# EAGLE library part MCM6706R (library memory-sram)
MEMORY

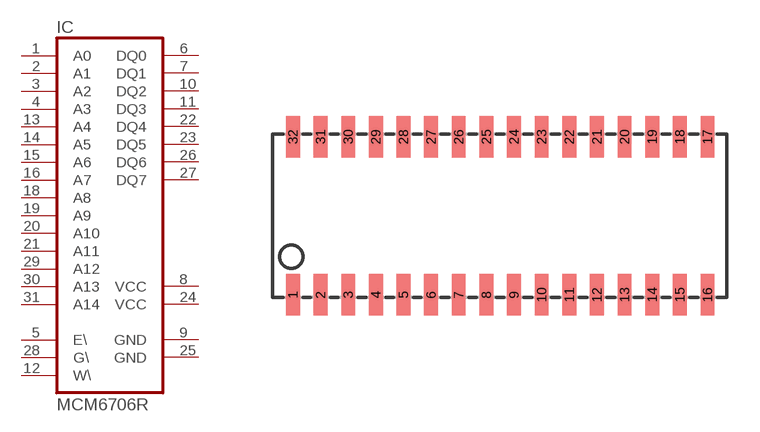
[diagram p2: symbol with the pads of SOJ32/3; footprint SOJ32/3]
Designator prefix IC

## MCM6706R  [SOJ32/3]
1  A0  in
2  A1  in
3  A2  in
4  A3  in
5  E\  in
6  DQ0
7  DQ1
8  VCC  pwr
9  GND  pwr
10  DQ2
11  DQ3
12  W\  in
13  A4  in
14  A5  in
15  A6  in
16  A7  in
18  A8  in
19  A9  in
20  A10  in
21  A11  in
22  DQ4
23  DQ5
24  VCC  pwr
25  GND  pwr
26  DQ6
27  DQ7
28  G\  in
29  A12  in
30  A13  in
31  A14  in

## Footprint SOJ32/3 (pad centres in mm)
Small Outline J-Bend
smd 0.635 x 1.905: 1 -8.89,-3.759; 2 -7.62,-3.759; 3 -6.35,-3.759; 4 -5.08,-3.759; 5 -3.81,-3.759; 6 -2.54,-3.759; 7 -1.27,-3.759; 8 0,-3.759; 9 1.27,-3.759; 10 2.54,-3.759; 11 3.81,-3.759; 12 5.08,-3.759; 13 6.35,-3.759; 14 7.62,-3.759; 15 8.89,-3.759; 16 10.16,-3.759; 17 10.16,3.505; 18 8.89,3.505; 19 7.62,3.505; 20 6.35,3.505; 21 5.08,3.505; 22 3.81,3.505; 23 2.54,3.505; 24 1.27,3.505; 25 0,3.505; 26 -1.27,3.505; 27 -2.54,3.505; 28 -3.81,3.505; 29 -5.08,3.505; 30 -6.35,3.505; 31 -7.62,3.505; 32 -8.89,3.505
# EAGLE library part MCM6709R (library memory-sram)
MEMORY

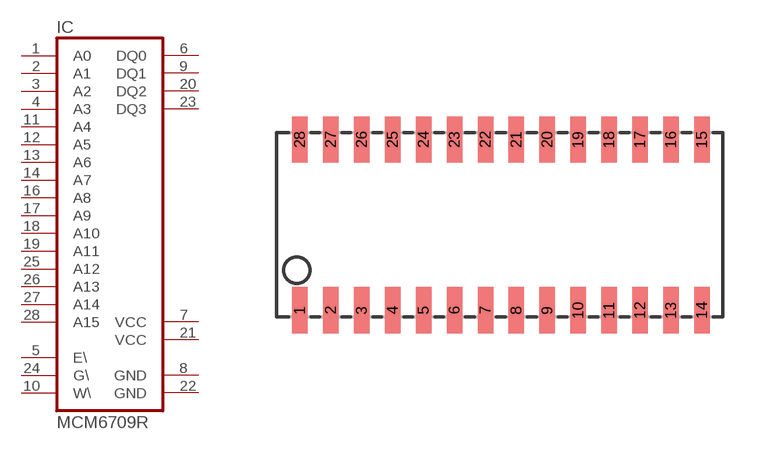
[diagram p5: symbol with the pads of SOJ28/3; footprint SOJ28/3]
Designator prefix IC

## MCM6709R  [SOJ28/3]
1  A0  in
2  A1  in
3  A2  in
4  A3  in
5  E\  in
6  DQ0
7  VCC  pwr
8  GND  pwr
9  DQ1
10  W\  in
11  A4  in
12  A5  in
13  A6  in
14  A7  in
16  A8  in
17  A9  in
18  A10  in
19  A11  in
20  DQ2
21  VCC  pwr
22  GND  pwr
23  DQ3
24  G\  in
25  A12  in
26  A13  in
27  A14  in
28  A15  in

## Footprint SOJ28/3 (pad centres in mm)
Small Outline J-Bend
smd 0.635 x 1.905: 1 -7.62,-3.505; 2 -6.35,-3.505; 3 -5.08,-3.505; 4 -3.81,-3.505; 5 -2.54,-3.505; 6 -1.27,-3.505; 7 0,-3.505; 8 1.27,-3.505; 9 2.54,-3.505; 10 3.81,-3.505; 11 5.08,-3.505; 12 6.35,-3.505; 13 7.62,-3.505; 14 8.89,-3.505; 15 8.89,3.505; 16 7.62,3.505; 17 6.35,3.505; 18 5.08,3.505; 19 3.81,3.505; 20 2.54,3.505; 21 1.27,3.505; 22 0,3.505; 23 -1.27,3.505; 24 -2.54,3.505; 25 -3.81,3.505; 26 -5.08,3.505; 27 -6.35,3.505; 28 -7.62,3.505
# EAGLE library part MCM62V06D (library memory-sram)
MEMORY

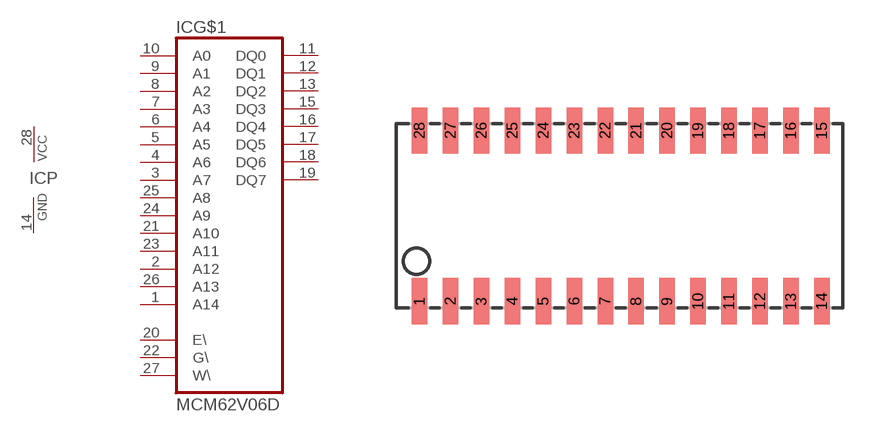
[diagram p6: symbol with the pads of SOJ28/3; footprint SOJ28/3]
Designator prefix IC; gates G$1=CM62V06D P=PWRN

## MCM62V06D  [SOJ28/3]
1  G$1:A14  in
2  G$1:A12  in
3  G$1:A7  in
4  G$1:A6  in
5  G$1:A5  in
6  G$1:A4  in
7  G$1:A3  in
8  G$1:A2  in
9  G$1:A1  in
10  G$1:A0  in
11  G$1:DQ0
12  G$1:DQ1
13  G$1:DQ2
14  P:GND  pwr
15  G$1:DQ3
16  G$1:DQ4
17  G$1:DQ5
18  G$1:DQ6
19  G$1:DQ7
20  G$1:E\  in
21  G$1:A10  in
22  G$1:G\  in
23  G$1:A11  in
24  G$1:A9  in
25  G$1:A8  in
26  G$1:A13  in
27  G$1:W\  in
28  P:VCC  pwr

## Footprint SOJ28/3 (pad centres in mm)
Small Outline J-Bend
smd 0.635 x 1.905: 1 -7.62,-3.505; 2 -6.35,-3.505; 3 -5.08,-3.505; 4 -3.81,-3.505; 5 -2.54,-3.505; 6 -1.27,-3.505; 7 0,-3.505; 8 1.27,-3.505; 9 2.54,-3.505; 10 3.81,-3.505; 11 5.08,-3.505; 12 6.35,-3.505; 13 7.62,-3.505; 14 8.89,-3.505; 15 8.89,3.505; 16 7.62,3.505; 17 6.35,3.505; 18 5.08,3.505; 19 3.81,3.505; 20 2.54,3.505; 21 1.27,3.505; 22 0,3.505; 23 -1.27,3.505; 24 -2.54,3.505; 25 -3.81,3.505; 26 -5.08,3.505; 27 -6.35,3.505; 28 -7.62,3.505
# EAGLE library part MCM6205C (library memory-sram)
MEMORY

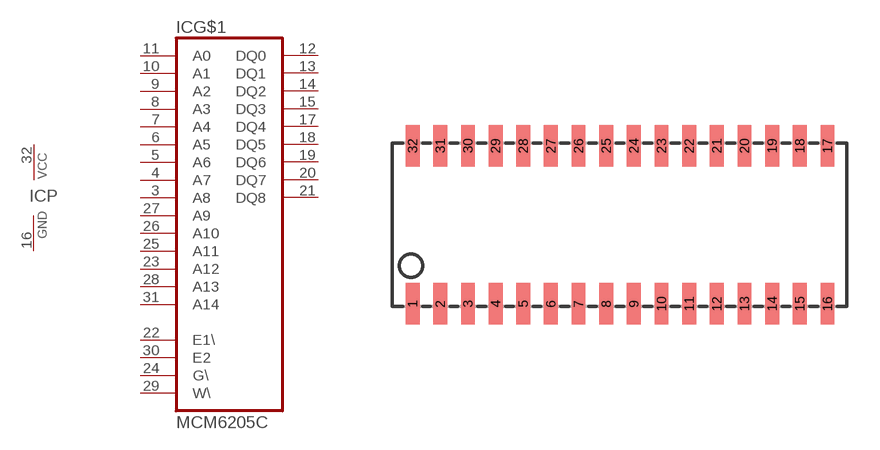
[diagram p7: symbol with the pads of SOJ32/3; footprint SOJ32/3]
Designator prefix IC; gates G$1=CM6205C P=PWRN

## MCM6205C  [SOJ32/3]
3  G$1:A8  in
4  G$1:A7  in
5  G$1:A6  in
6  G$1:A5  in
7  G$1:A4  in
8  G$1:A3  in
9  G$1:A2  in
10  G$1:A1  in
11  G$1:A0  in
12  G$1:DQ0
13  G$1:DQ1
14  G$1:DQ2
15  G$1:DQ3
16  P:GND  pwr
17  G$1:DQ4
18  G$1:DQ5
19  G$1:DQ6
20  G$1:DQ7
21  G$1:DQ8
22  G$1:E1\  in
23  G$1:A12  in
24  G$1:G\  in
25  G$1:A11  in
26  G$1:A10  in
27  G$1:A9  in
28  G$1:A13  in
29  G$1:W\  in
30  G$1:E2  in
31  G$1:A14  in
32  P:VCC  pwr

## Footprint SOJ32/3 (pad centres in mm)
Small Outline J-Bend
smd 0.635 x 1.905: 1 -8.89,-3.759; 2 -7.62,-3.759; 3 -6.35,-3.759; 4 -5.08,-3.759; 5 -3.81,-3.759; 6 -2.54,-3.759; 7 -1.27,-3.759; 8 0,-3.759; 9 1.27,-3.759; 10 2.54,-3.759; 11 3.81,-3.759; 12 5.08,-3.759; 13 6.35,-3.759; 14 7.62,-3.759; 15 8.89,-3.759; 16 10.16,-3.759; 17 10.16,3.505; 18 8.89,3.505; 19 7.62,3.505; 20 6.35,3.505; 21 5.08,3.505; 22 3.81,3.505; 23 2.54,3.505; 24 1.27,3.505; 25 0,3.505; 26 -1.27,3.505; 27 -2.54,3.505; 28 -3.81,3.505; 29 -5.08,3.505; 30 -6.35,3.505; 31 -7.62,3.505; 32 -8.89,3.505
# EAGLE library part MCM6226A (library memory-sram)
MEMORY

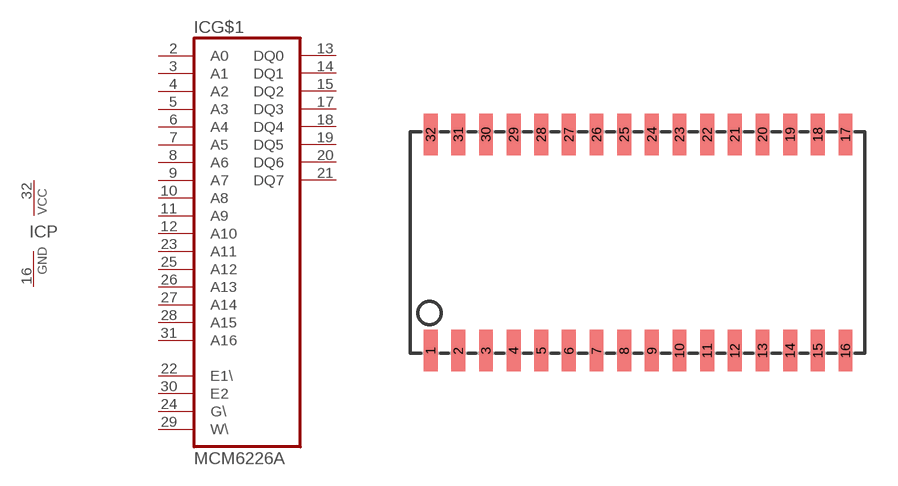
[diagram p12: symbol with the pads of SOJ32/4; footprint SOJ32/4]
Designator prefix IC; gates G$1=CM6226A P=PWRN

## MCM6226A  [SOJ32/4]
2  G$1:A0  in
3  G$1:A1  in
4  G$1:A2  in
5  G$1:A3  in
6  G$1:A4  in
7  G$1:A5  in
8  G$1:A6  in
9  G$1:A7  in
10  G$1:A8  in
11  G$1:A9  in
12  G$1:A10  in
13  G$1:DQ0
14  G$1:DQ1
15  G$1:DQ2
16  P:GND  pwr
17  G$1:DQ3
18  G$1:DQ4
19  G$1:DQ5
20  G$1:DQ6
21  G$1:DQ7
22  G$1:E1\  in
23  G$1:A11  in
24  G$1:G\  in
25  G$1:A12  in
26  G$1:A13  in
27  G$1:A14  in
28  G$1:A15  in
29  G$1:W\  in
30  G$1:E2  in
31  G$1:A16  in
32  P:VCC  pwr

## Footprint SOJ32/4 (pad centres in mm)
Small Outline J-Bend
smd 0.635 x 1.905: 1 -8.89,-4.902; 2 -7.62,-4.902; 3 -6.35,-4.902; 4 -5.08,-4.902; 5 -3.81,-4.902; 6 -2.54,-4.902; 7 -1.27,-4.902; 8 0,-4.902; 9 1.27,-4.902; 10 2.54,-4.902; 11 3.81,-4.902; 12 5.08,-4.902; 13 6.35,-4.902; 14 7.62,-4.902; 15 8.89,-4.902; 16 10.16,-4.902; 17 10.16,5.029; 18 8.89,5.029; 19 7.62,5.029; 20 6.35,5.029; 21 5.08,5.029; 22 3.81,5.029; 23 2.54,5.029; 24 1.27,5.029; 25 0,5.029; 26 -1.27,5.029; 27 -2.54,5.029; 28 -3.81,5.029; 29 -5.08,5.029; 30 -6.35,5.029; 31 -7.62,5.029; 32 -8.89,5.029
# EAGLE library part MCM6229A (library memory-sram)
MEMORY

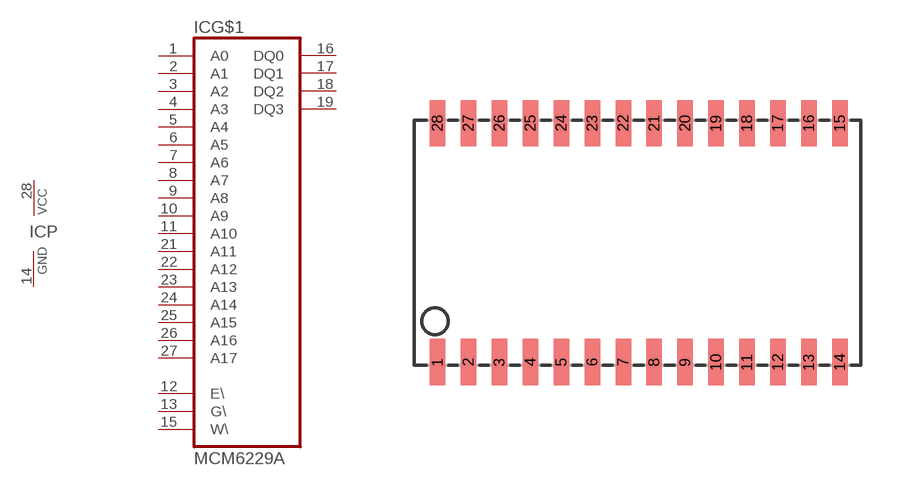
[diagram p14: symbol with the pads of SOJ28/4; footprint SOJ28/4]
Designator prefix IC; gates G$1=CM6229A P=PWRN

## MCM6229A  [SOJ28/4]
1  G$1:A0  in
2  G$1:A1  in
3  G$1:A2  in
4  G$1:A3  in
5  G$1:A4  in
6  G$1:A5  in
7  G$1:A6  in
8  G$1:A7  in
9  G$1:A8  in
10  G$1:A9  in
11  G$1:A10  in
12  G$1:E\  in
13  G$1:G\  in
14  P:GND  pwr
15  G$1:W\  in
16  G$1:DQ0
17  G$1:DQ1
18  G$1:DQ2
19  G$1:DQ3
21  G$1:A11  in
22  G$1:A12  in
23  G$1:A13  in
24  G$1:A14  in
25  G$1:A15  in
26  G$1:A16  in
27  G$1:A17  in
28  P:VCC  pwr

## Footprint SOJ28/4 (pad centres in mm)
Small Outline J-Bend
smd 0.635 x 1.905: 1 -7.62,-5.156; 2 -6.35,-5.156; 3 -5.08,-5.156; 4 -3.81,-5.156; 5 -2.54,-5.156; 6 -1.27,-5.156; 7 0,-5.156; 8 1.27,-5.156; 9 2.54,-5.156; 10 3.81,-5.156; 11 5.08,-5.156; 12 6.35,-5.156; 13 7.62,-5.156; 14 8.89,-5.156; 15 8.89,4.648; 16 7.62,4.648; 17 6.35,4.648; 18 5.08,4.648; 19 3.81,4.648; 20 2.54,4.648; 21 1.27,4.648; 22 0,4.648; 23 -1.27,4.648; 24 -2.54,4.648; 25 -3.81,4.648; 26 -5.08,4.648; 27 -6.35,4.648; 28 -7.62,4.648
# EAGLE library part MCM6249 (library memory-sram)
MEMORY

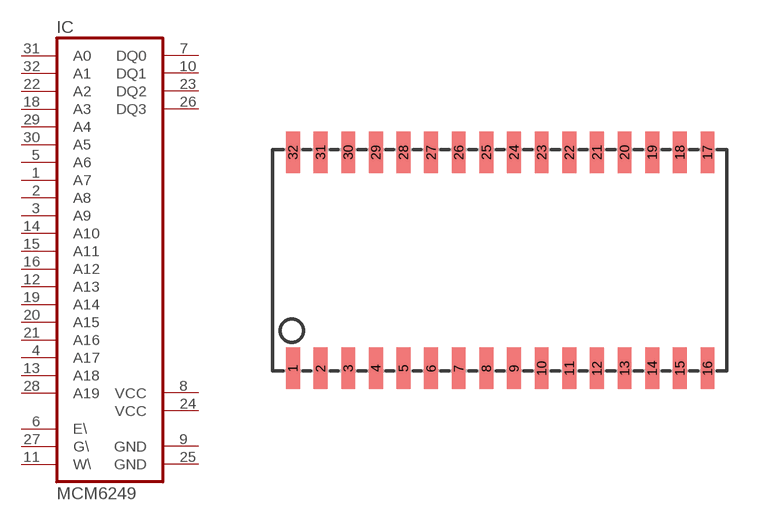
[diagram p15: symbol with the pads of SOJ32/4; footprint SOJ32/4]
Designator prefix IC

## MCM6249  [SOJ32/4]
1  A7  in
2  A8  in
3  A9  in
4  A17  in
5  A6  in
6  E\  in
7  DQ0
8  VCC  pwr
9  GND  pwr
10  DQ1
11  W\  in
12  A13  in
13  A18  in
14  A10  in
15  A11  in
16  A12  in
18  A3  in
19  A14  in
20  A15  in
21  A16  in
22  A2  in
23  DQ2
24  VCC  pwr
25  GND  pwr
26  DQ3
27  G\  in
28  A19  in
29  A4  in
30  A5  in
31  A0  in
32  A1  in

## Footprint SOJ32/4 (pad centres in mm)
Small Outline J-Bend
smd 0.635 x 1.905: 1 -8.89,-4.902; 2 -7.62,-4.902; 3 -6.35,-4.902; 4 -5.08,-4.902; 5 -3.81,-4.902; 6 -2.54,-4.902; 7 -1.27,-4.902; 8 0,-4.902; 9 1.27,-4.902; 10 2.54,-4.902; 11 3.81,-4.902; 12 5.08,-4.902; 13 6.35,-4.902; 14 7.62,-4.902; 15 8.89,-4.902; 16 10.16,-4.902; 17 10.16,5.029; 18 8.89,5.029; 19 7.62,5.029; 20 6.35,5.029; 21 5.08,5.029; 22 3.81,5.029; 23 2.54,5.029; 24 1.27,5.029; 25 0,5.029; 26 -1.27,5.029; 27 -2.54,5.029; 28 -3.81,5.029; 29 -5.08,5.029; 30 -6.35,5.029; 31 -7.62,5.029; 32 -8.89,5.029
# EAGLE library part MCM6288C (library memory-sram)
MEMORY

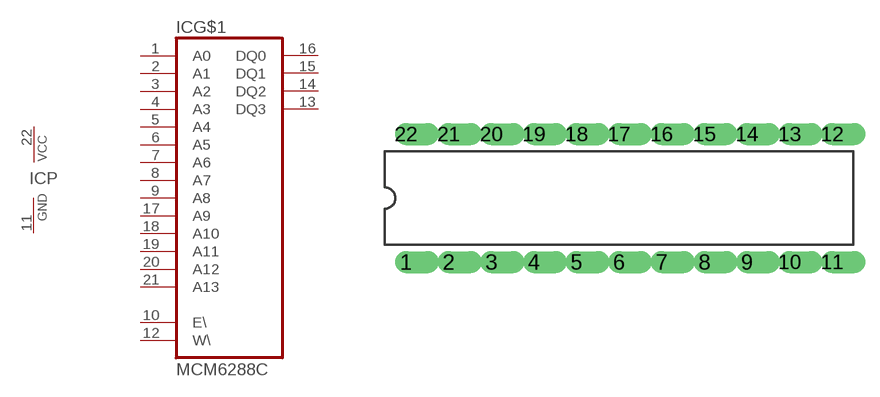
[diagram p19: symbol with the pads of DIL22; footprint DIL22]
Designator prefix IC; gates G$1=CM6288C P=PWRN

## MCM6288C  [DIL22]
1  G$1:A0  in
2  G$1:A1  in
3  G$1:A2  in
4  G$1:A3  in
5  G$1:A4  in
6  G$1:A5  in
7  G$1:A6  in
8  G$1:A7  in
9  G$1:A8  in
10  G$1:E\  in
11  P:GND  pwr
12  G$1:W\  in
13  G$1:DQ3
14  G$1:DQ2
15  G$1:DQ1
16  G$1:DQ0
17  G$1:A9  in
18  G$1:A10  in
19  G$1:A11  in
20  G$1:A12  in
21  G$1:A13  in
22  P:VCC  pwr

## Footprint DIL22 (pad centres in mm)
Dual In Line
drill 0.813 offset: 1 -12.7,-3.81; 2 -10.16,-3.81; 3 -7.62,-3.81; 4 -5.08,-3.81; 5 -2.54,-3.81; 6 0,-3.81; 7 2.54,-3.81; 8 5.08,-3.81; 9 7.62,-3.81; 10 10.16,-3.81; 11 12.7,-3.81; 12 12.7,3.81; 13 10.16,3.81; 14 7.62,3.81; 15 5.08,3.81; 16 2.54,3.81; 17 0,3.81; 18 -2.54,3.81; 19 -5.08,3.81; 20 -7.62,3.81; 21 -10.16,3.81; 22 -12.7,3.81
